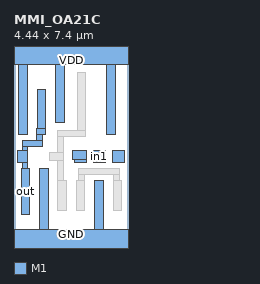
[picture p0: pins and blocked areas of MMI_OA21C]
MACRO MMI_OA21C
	CLASS CORE ;
	FOREIGN MMI_OA21C 0 0 ;
	SIZE 4.44 BY 7.4 ;
	SYMMETRY X Y ;
	SITE CORE1 ;
	PIN out
		DIRECTION output ;
		USE SIGNAL ;
		PORT
			LAYER M1 ;
			RECT 0.9 4.42 1.24 5.95 ;
			LAYER M1 ;
			RECT 0.895 4.19 1.24 4.42 ;
			LAYER M1 ;
			RECT 0.895 3.94 1.125 4.19 ;
			LAYER M1 ;
			RECT 0.315 3.71 1.125 3.94 ;
			LAYER M1 ;
			RECT 0.315 3.555 0.545 3.71 ;
			LAYER M1 ;
			RECT 0.145 3.105 0.545 3.555 ;
			LAYER M1 ;
			RECT 0.315 2.85 0.545 3.105 ;
			LAYER M1 ;
			RECT 0.28 1.09 0.62 2.85 ;
		END
		AntennaDiffArea 1.8768 ;
	END out
	PIN in1
		DIRECTION input ;
		USE SIGNAL ;
		PORT
			LAYER M1 ;
			RECT 3.105 3.495 3.555 3.55 ;
			LAYER M1 ;
			RECT 3.075 3.155 3.555 3.495 ;
			LAYER M1 ;
			RECT 3.105 3.1 3.555 3.155 ;
		END
		AntennaGateArea 0.6696 ;
	END in1
	PIN GND
		DIRECTION inout ;
		USE GROUND ;
		PORT
			LAYER M1 ;
			RECT 1 0.5 1.34 2.85 ;
			LAYER M1 ;
			RECT 3.14 0.5 3.48 2.4 ;
			LAYER M1 ;
			RECT 0 -0.5 4.44 0.5 ;
		END
	END GND
	PIN in2
		DIRECTION input ;
		USE SIGNAL ;
		PORT
			LAYER M1 ;
			RECT 3.845 3.105 4.295 3.555 ;
		END
		AntennaGateArea 0.6696 ;
	END in2
	PIN VDD
		DIRECTION inout ;
		USE POWER ;
		PORT
			LAYER M1 ;
			RECT 0 6.9 4.44 7.9 ;
			LAYER M1 ;
			RECT 0.18 4.19 0.52 6.9 ;
			LAYER M1 ;
			RECT 1.62 4.67 1.96 6.9 ;
			LAYER M1 ;
			RECT 3.605 4.19 3.945 6.9 ;
		END
	END VDD
	PIN in0
		DIRECTION input ;
		USE SIGNAL ;
		PORT
			LAYER M1 ;
			RECT 2.26 3.215 2.815 3.555 ;
			LAYER M1 ;
			RECT 2.365 3.105 2.815 3.215 ;
		END
		AntennaGateArea 0.4464 ;
	END in0
	OBS
		LAYER M1 ;
		RECT 2.455 4.345 2.795 6.59 ;
		LAYER M1 ;
		RECT 1.7 4.115 2.795 4.345 ;
		LAYER M1 ;
		RECT 1.7 3.5 1.93 4.115 ;
		LAYER M1 ;
		RECT 1.365 3.16 1.93 3.5 ;
		LAYER M1 ;
		RECT 1.7 2.4 1.93 3.16 ;
		LAYER M1 ;
		RECT 2.53 2.64 4.09 2.87 ;
		LAYER M1 ;
		RECT 2.53 2.4 2.76 2.64 ;
		LAYER M1 ;
		RECT 3.86 2.4 4.09 2.64 ;
		LAYER M1 ;
		RECT 1.7 1.24 2.04 2.4 ;
		LAYER M1 ;
		RECT 2.42 1.24 2.76 2.4 ;
		LAYER M1 ;
		RECT 3.86 1.24 4.2 2.4 ;
	END
END MMI_OA21C
